VERSION 5.7 ;
BUSBITCHARS "[]" ;
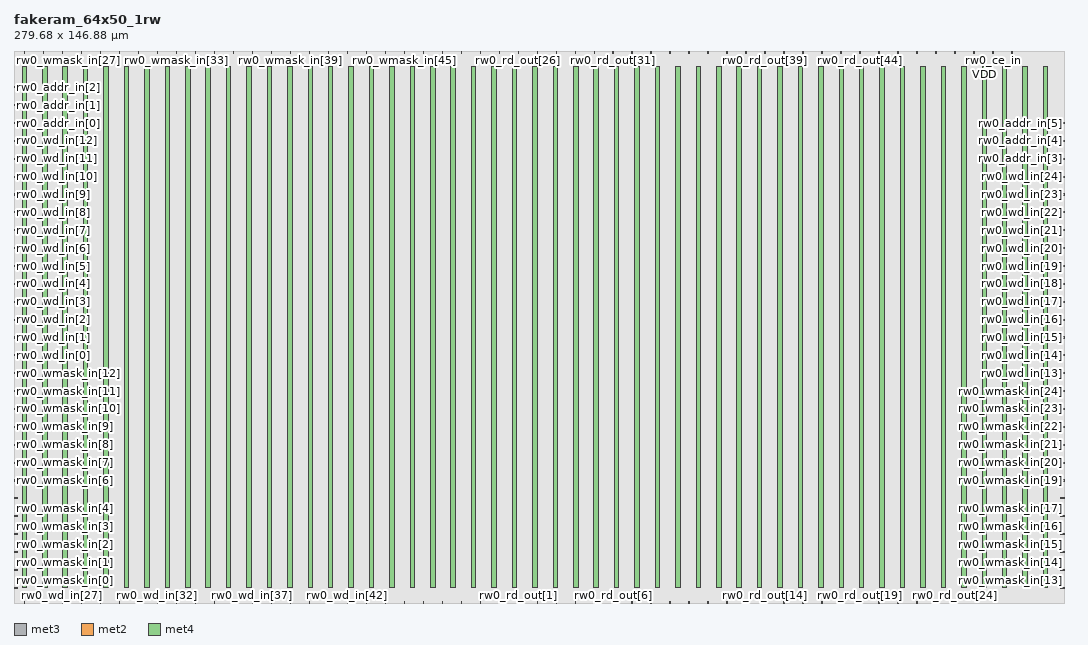
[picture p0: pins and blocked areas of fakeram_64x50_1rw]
MACRO fakeram_64x50_1rw
  FOREIGN fakeram_64x50_1rw 0 0 ;
  SYMMETRY X Y R90 ;
  SIZE 279.680 BY 146.880 ;
  CLASS BLOCK ;
  PIN rw0_wmask_in[0]
    DIRECTION INPUT ;
    USE SIGNAL ;
    SHAPE ABUTMENT ;
    PORT
      LAYER met3 ;
      RECT 0.000 3.930 0.900 4.230 ;
    END
  END rw0_wmask_in[0]
  PIN rw0_wmask_in[1]
    DIRECTION INPUT ;
    USE SIGNAL ;
    SHAPE ABUTMENT ;
    PORT
      LAYER met3 ;
      RECT 0.000 8.690 0.900 8.990 ;
    END
  END rw0_wmask_in[1]
  PIN rw0_wmask_in[2]
    DIRECTION INPUT ;
    USE SIGNAL ;
    SHAPE ABUTMENT ;
    PORT
      LAYER met3 ;
      RECT 0.000 13.450 0.900 13.750 ;
    END
  END rw0_wmask_in[2]
  PIN rw0_wmask_in[3]
    DIRECTION INPUT ;
    USE SIGNAL ;
    SHAPE ABUTMENT ;
    PORT
      LAYER met3 ;
      RECT 0.000 18.210 0.900 18.510 ;
    END
  END rw0_wmask_in[3]
  PIN rw0_wmask_in[4]
    DIRECTION INPUT ;
    USE SIGNAL ;
    SHAPE ABUTMENT ;
    PORT
      LAYER met3 ;
      RECT 0.000 22.970 0.900 23.270 ;
    END
  END rw0_wmask_in[4]
  PIN rw0_wmask_in[5]
    DIRECTION INPUT ;
    USE SIGNAL ;
    SHAPE ABUTMENT ;
    PORT
      LAYER met3 ;
      RECT 0.000 27.730 0.900 28.030 ;
    END
  END rw0_wmask_in[5]
  PIN rw0_wmask_in[6]
    DIRECTION INPUT ;
    USE SIGNAL ;
    SHAPE ABUTMENT ;
    PORT
      LAYER met3 ;
      RECT 0.000 32.490 0.900 32.790 ;
    END
  END rw0_wmask_in[6]
  PIN rw0_wmask_in[7]
    DIRECTION INPUT ;
    USE SIGNAL ;
    SHAPE ABUTMENT ;
    PORT
      LAYER met3 ;
      RECT 0.000 37.250 0.900 37.550 ;
    END
  END rw0_wmask_in[7]
  PIN rw0_wmask_in[8]
    DIRECTION INPUT ;
    USE SIGNAL ;
    SHAPE ABUTMENT ;
    PORT
      LAYER met3 ;
      RECT 0.000 42.010 0.900 42.310 ;
    END
  END rw0_wmask_in[8]
  PIN rw0_wmask_in[9]
    DIRECTION INPUT ;
    USE SIGNAL ;
    SHAPE ABUTMENT ;
    PORT
      LAYER met3 ;
      RECT 0.000 46.770 0.900 47.070 ;
    END
  END rw0_wmask_in[9]
  PIN rw0_wmask_in[10]
    DIRECTION INPUT ;
    USE SIGNAL ;
    SHAPE ABUTMENT ;
    PORT
      LAYER met3 ;
      RECT 0.000 51.530 0.900 51.830 ;
    END
  END rw0_wmask_in[10]
  PIN rw0_wmask_in[11]
    DIRECTION INPUT ;
    USE SIGNAL ;
    SHAPE ABUTMENT ;
    PORT
      LAYER met3 ;
      RECT 0.000 56.290 0.900 56.590 ;
    END
  END rw0_wmask_in[11]
  PIN rw0_wmask_in[12]
    DIRECTION INPUT ;
    USE SIGNAL ;
    SHAPE ABUTMENT ;
    PORT
      LAYER met3 ;
      RECT 0.000 61.050 0.900 61.350 ;
    END
  END rw0_wmask_in[12]
  PIN rw0_wmask_in[13]
    DIRECTION INPUT ;
    USE SIGNAL ;
    SHAPE ABUTMENT ;
    PORT
      LAYER met3 ;
      RECT 278.780 3.930 279.680 4.230 ;
    END
  END rw0_wmask_in[13]
  PIN rw0_wmask_in[14]
    DIRECTION INPUT ;
    USE SIGNAL ;
    SHAPE ABUTMENT ;
    PORT
      LAYER met3 ;
      RECT 278.780 8.690 279.680 8.990 ;
    END
  END rw0_wmask_in[14]
  PIN rw0_wmask_in[15]
    DIRECTION INPUT ;
    USE SIGNAL ;
    SHAPE ABUTMENT ;
    PORT
      LAYER met3 ;
      RECT 278.780 13.450 279.680 13.750 ;
    END
  END rw0_wmask_in[15]
  PIN rw0_wmask_in[16]
    DIRECTION INPUT ;
    USE SIGNAL ;
    SHAPE ABUTMENT ;
    PORT
      LAYER met3 ;
      RECT 278.780 18.210 279.680 18.510 ;
    END
  END rw0_wmask_in[16]
  PIN rw0_wmask_in[17]
    DIRECTION INPUT ;
    USE SIGNAL ;
    SHAPE ABUTMENT ;
    PORT
      LAYER met3 ;
      RECT 278.780 22.970 279.680 23.270 ;
    END
  END rw0_wmask_in[17]
  PIN rw0_wmask_in[18]
    DIRECTION INPUT ;
    USE SIGNAL ;
    SHAPE ABUTMENT ;
    PORT
      LAYER met3 ;
      RECT 278.780 27.730 279.680 28.030 ;
    END
  END rw0_wmask_in[18]
  PIN rw0_wmask_in[19]
    DIRECTION INPUT ;
    USE SIGNAL ;
    SHAPE ABUTMENT ;
    PORT
      LAYER met3 ;
      RECT 278.780 32.490 279.680 32.790 ;
    END
  END rw0_wmask_in[19]
  PIN rw0_wmask_in[20]
    DIRECTION INPUT ;
    USE SIGNAL ;
    SHAPE ABUTMENT ;
    PORT
      LAYER met3 ;
      RECT 278.780 37.250 279.680 37.550 ;
    END
  END rw0_wmask_in[20]
  PIN rw0_wmask_in[21]
    DIRECTION INPUT ;
    USE SIGNAL ;
    SHAPE ABUTMENT ;
    PORT
      LAYER met3 ;
      RECT 278.780 42.010 279.680 42.310 ;
    END
  END rw0_wmask_in[21]
  PIN rw0_wmask_in[22]
    DIRECTION INPUT ;
    USE SIGNAL ;
    SHAPE ABUTMENT ;
    PORT
      LAYER met3 ;
      RECT 278.780 46.770 279.680 47.070 ;
    END
  END rw0_wmask_in[22]
  PIN rw0_wmask_in[23]
    DIRECTION INPUT ;
    USE SIGNAL ;
    SHAPE ABUTMENT ;
    PORT
      LAYER met3 ;
      RECT 278.780 51.530 279.680 51.830 ;
    END
  END rw0_wmask_in[23]
  PIN rw0_wmask_in[24]
    DIRECTION INPUT ;
    USE SIGNAL ;
    SHAPE ABUTMENT ;
    PORT
      LAYER met3 ;
      RECT 278.780 56.290 279.680 56.590 ;
    END
  END rw0_wmask_in[24]
  PIN rw0_wmask_in[25]
    DIRECTION INPUT ;
    USE SIGNAL ;
    SHAPE ABUTMENT ;
    PORT
      LAYER met2 ;
      RECT 2.690 146.460 2.830 146.880 ;
    END
  END rw0_wmask_in[25]
  PIN rw0_wmask_in[26]
    DIRECTION INPUT ;
    USE SIGNAL ;
    SHAPE ABUTMENT ;
    PORT
      LAYER met2 ;
      RECT 7.750 146.460 7.890 146.880 ;
    END
  END rw0_wmask_in[26]
  PIN rw0_wmask_in[27]
    DIRECTION INPUT ;
    USE SIGNAL ;
    SHAPE ABUTMENT ;
    PORT
      LAYER met2 ;
      RECT 12.810 146.460 12.950 146.880 ;
    END
  END rw0_wmask_in[27]
  PIN rw0_wmask_in[28]
    DIRECTION INPUT ;
    USE SIGNAL ;
    SHAPE ABUTMENT ;
    PORT
      LAYER met2 ;
      RECT 17.870 146.460 18.010 146.880 ;
    END
  END rw0_wmask_in[28]
  PIN rw0_wmask_in[29]
    DIRECTION INPUT ;
    USE SIGNAL ;
    SHAPE ABUTMENT ;
    PORT
      LAYER met2 ;
      RECT 22.930 146.460 23.070 146.880 ;
    END
  END rw0_wmask_in[29]
  PIN rw0_wmask_in[30]
    DIRECTION INPUT ;
    USE SIGNAL ;
    SHAPE ABUTMENT ;
    PORT
      LAYER met2 ;
      RECT 27.990 146.460 28.130 146.880 ;
    END
  END rw0_wmask_in[30]
  PIN rw0_wmask_in[31]
    DIRECTION INPUT ;
    USE SIGNAL ;
    SHAPE ABUTMENT ;
    PORT
      LAYER met2 ;
      RECT 33.050 146.460 33.190 146.880 ;
    END
  END rw0_wmask_in[31]
  PIN rw0_wmask_in[32]
    DIRECTION INPUT ;
    USE SIGNAL ;
    SHAPE ABUTMENT ;
    PORT
      LAYER met2 ;
      RECT 38.110 146.460 38.250 146.880 ;
    END
  END rw0_wmask_in[32]
  PIN rw0_wmask_in[33]
    DIRECTION INPUT ;
    USE SIGNAL ;
    SHAPE ABUTMENT ;
    PORT
      LAYER met2 ;
      RECT 43.170 146.460 43.310 146.880 ;
    END
  END rw0_wmask_in[33]
  PIN rw0_wmask_in[34]
    DIRECTION INPUT ;
    USE SIGNAL ;
    SHAPE ABUTMENT ;
    PORT
      LAYER met2 ;
      RECT 48.230 146.460 48.370 146.880 ;
    END
  END rw0_wmask_in[34]
  PIN rw0_wmask_in[35]
    DIRECTION INPUT ;
    USE SIGNAL ;
    SHAPE ABUTMENT ;
    PORT
      LAYER met2 ;
      RECT 53.290 146.460 53.430 146.880 ;
    END
  END rw0_wmask_in[35]
  PIN rw0_wmask_in[36]
    DIRECTION INPUT ;
    USE SIGNAL ;
    SHAPE ABUTMENT ;
    PORT
      LAYER met2 ;
      RECT 58.350 146.460 58.490 146.880 ;
    END
  END rw0_wmask_in[36]
  PIN rw0_wmask_in[37]
    DIRECTION INPUT ;
    USE SIGNAL ;
    SHAPE ABUTMENT ;
    PORT
      LAYER met2 ;
      RECT 63.410 146.460 63.550 146.880 ;
    END
  END rw0_wmask_in[37]
  PIN rw0_wmask_in[38]
    DIRECTION INPUT ;
    USE SIGNAL ;
    SHAPE ABUTMENT ;
    PORT
      LAYER met2 ;
      RECT 68.470 146.460 68.610 146.880 ;
    END
  END rw0_wmask_in[38]
  PIN rw0_wmask_in[39]
    DIRECTION INPUT ;
    USE SIGNAL ;
    SHAPE ABUTMENT ;
    PORT
      LAYER met2 ;
      RECT 73.530 146.460 73.670 146.880 ;
    END
  END rw0_wmask_in[39]
  PIN rw0_wmask_in[40]
    DIRECTION INPUT ;
    USE SIGNAL ;
    SHAPE ABUTMENT ;
    PORT
      LAYER met2 ;
      RECT 78.590 146.460 78.730 146.880 ;
    END
  END rw0_wmask_in[40]
  PIN rw0_wmask_in[41]
    DIRECTION INPUT ;
    USE SIGNAL ;
    SHAPE ABUTMENT ;
    PORT
      LAYER met2 ;
      RECT 83.650 146.460 83.790 146.880 ;
    END
  END rw0_wmask_in[41]
  PIN rw0_wmask_in[42]
    DIRECTION INPUT ;
    USE SIGNAL ;
    SHAPE ABUTMENT ;
    PORT
      LAYER met2 ;
      RECT 88.710 146.460 88.850 146.880 ;
    END
  END rw0_wmask_in[42]
  PIN rw0_wmask_in[43]
    DIRECTION INPUT ;
    USE SIGNAL ;
    SHAPE ABUTMENT ;
    PORT
      LAYER met2 ;
      RECT 93.770 146.460 93.910 146.880 ;
    END
  END rw0_wmask_in[43]
  PIN rw0_wmask_in[44]
    DIRECTION INPUT ;
    USE SIGNAL ;
    SHAPE ABUTMENT ;
    PORT
      LAYER met2 ;
      RECT 98.830 146.460 98.970 146.880 ;
    END
  END rw0_wmask_in[44]
  PIN rw0_wmask_in[45]
    DIRECTION INPUT ;
    USE SIGNAL ;
    SHAPE ABUTMENT ;
    PORT
      LAYER met2 ;
      RECT 103.890 146.460 104.030 146.880 ;
    END
  END rw0_wmask_in[45]
  PIN rw0_wmask_in[46]
    DIRECTION INPUT ;
    USE SIGNAL ;
    SHAPE ABUTMENT ;
    PORT
      LAYER met2 ;
      RECT 108.950 146.460 109.090 146.880 ;
    END
  END rw0_wmask_in[46]
  PIN rw0_wmask_in[47]
    DIRECTION INPUT ;
    USE SIGNAL ;
    SHAPE ABUTMENT ;
    PORT
      LAYER met2 ;
      RECT 114.010 146.460 114.150 146.880 ;
    END
  END rw0_wmask_in[47]
  PIN rw0_wmask_in[48]
    DIRECTION INPUT ;
    USE SIGNAL ;
    SHAPE ABUTMENT ;
    PORT
      LAYER met2 ;
      RECT 119.070 146.460 119.210 146.880 ;
    END
  END rw0_wmask_in[48]
  PIN rw0_wmask_in[49]
    DIRECTION INPUT ;
    USE SIGNAL ;
    SHAPE ABUTMENT ;
    PORT
      LAYER met2 ;
      RECT 124.130 146.460 124.270 146.880 ;
    END
  END rw0_wmask_in[49]
  PIN rw0_wd_in[0]
    DIRECTION INPUT ;
    USE SIGNAL ;
    SHAPE ABUTMENT ;
    PORT
      LAYER met3 ;
      RECT 0.000 65.810 0.900 66.110 ;
    END
  END rw0_wd_in[0]
  PIN rw0_wd_in[1]
    DIRECTION INPUT ;
    USE SIGNAL ;
    SHAPE ABUTMENT ;
    PORT
      LAYER met3 ;
      RECT 0.000 70.570 0.900 70.870 ;
    END
  END rw0_wd_in[1]
  PIN rw0_wd_in[2]
    DIRECTION INPUT ;
    USE SIGNAL ;
    SHAPE ABUTMENT ;
    PORT
      LAYER met3 ;
      RECT 0.000 75.330 0.900 75.630 ;
    END
  END rw0_wd_in[2]
  PIN rw0_wd_in[3]
    DIRECTION INPUT ;
    USE SIGNAL ;
    SHAPE ABUTMENT ;
    PORT
      LAYER met3 ;
      RECT 0.000 80.090 0.900 80.390 ;
    END
  END rw0_wd_in[3]
  PIN rw0_wd_in[4]
    DIRECTION INPUT ;
    USE SIGNAL ;
    SHAPE ABUTMENT ;
    PORT
      LAYER met3 ;
      RECT 0.000 84.850 0.900 85.150 ;
    END
  END rw0_wd_in[4]
  PIN rw0_wd_in[5]
    DIRECTION INPUT ;
    USE SIGNAL ;
    SHAPE ABUTMENT ;
    PORT
      LAYER met3 ;
      RECT 0.000 89.610 0.900 89.910 ;
    END
  END rw0_wd_in[5]
  PIN rw0_wd_in[6]
    DIRECTION INPUT ;
    USE SIGNAL ;
    SHAPE ABUTMENT ;
    PORT
      LAYER met3 ;
      RECT 0.000 94.370 0.900 94.670 ;
    END
  END rw0_wd_in[6]
  PIN rw0_wd_in[7]
    DIRECTION INPUT ;
    USE SIGNAL ;
    SHAPE ABUTMENT ;
    PORT
      LAYER met3 ;
      RECT 0.000 99.130 0.900 99.430 ;
    END
  END rw0_wd_in[7]
  PIN rw0_wd_in[8]
    DIRECTION INPUT ;
    USE SIGNAL ;
    SHAPE ABUTMENT ;
    PORT
      LAYER met3 ;
      RECT 0.000 103.890 0.900 104.190 ;
    END
  END rw0_wd_in[8]
  PIN rw0_wd_in[9]
    DIRECTION INPUT ;
    USE SIGNAL ;
    SHAPE ABUTMENT ;
    PORT
      LAYER met3 ;
      RECT 0.000 108.650 0.900 108.950 ;
    END
  END rw0_wd_in[9]
  PIN rw0_wd_in[10]
    DIRECTION INPUT ;
    USE SIGNAL ;
    SHAPE ABUTMENT ;
    PORT
      LAYER met3 ;
      RECT 0.000 113.410 0.900 113.710 ;
    END
  END rw0_wd_in[10]
  PIN rw0_wd_in[11]
    DIRECTION INPUT ;
    USE SIGNAL ;
    SHAPE ABUTMENT ;
    PORT
      LAYER met3 ;
      RECT 0.000 118.170 0.900 118.470 ;
    END
  END rw0_wd_in[11]
  PIN rw0_wd_in[12]
    DIRECTION INPUT ;
    USE SIGNAL ;
    SHAPE ABUTMENT ;
    PORT
      LAYER met3 ;
      RECT 0.000 122.930 0.900 123.230 ;
    END
  END rw0_wd_in[12]
  PIN rw0_wd_in[13]
    DIRECTION INPUT ;
    USE SIGNAL ;
    SHAPE ABUTMENT ;
    PORT
      LAYER met3 ;
      RECT 278.780 61.050 279.680 61.350 ;
    END
  END rw0_wd_in[13]
  PIN rw0_wd_in[14]
    DIRECTION INPUT ;
    USE SIGNAL ;
    SHAPE ABUTMENT ;
    PORT
      LAYER met3 ;
      RECT 278.780 65.810 279.680 66.110 ;
    END
  END rw0_wd_in[14]
  PIN rw0_wd_in[15]
    DIRECTION INPUT ;
    USE SIGNAL ;
    SHAPE ABUTMENT ;
    PORT
      LAYER met3 ;
      RECT 278.780 70.570 279.680 70.870 ;
    END
  END rw0_wd_in[15]
  PIN rw0_wd_in[16]
    DIRECTION INPUT ;
    USE SIGNAL ;
    SHAPE ABUTMENT ;
    PORT
      LAYER met3 ;
      RECT 278.780 75.330 279.680 75.630 ;
    END
  END rw0_wd_in[16]
  PIN rw0_wd_in[17]
    DIRECTION INPUT ;
    USE SIGNAL ;
    SHAPE ABUTMENT ;
    PORT
      LAYER met3 ;
      RECT 278.780 80.090 279.680 80.390 ;
    END
  END rw0_wd_in[17]
  PIN rw0_wd_in[18]
    DIRECTION INPUT ;
    USE SIGNAL ;
    SHAPE ABUTMENT ;
    PORT
      LAYER met3 ;
      RECT 278.780 84.850 279.680 85.150 ;
    END
  END rw0_wd_in[18]
  PIN rw0_wd_in[19]
    DIRECTION INPUT ;
    USE SIGNAL ;
    SHAPE ABUTMENT ;
    PORT
      LAYER met3 ;
      RECT 278.780 89.610 279.680 89.910 ;
    END
  END rw0_wd_in[19]
  PIN rw0_wd_in[20]
    DIRECTION INPUT ;
    USE SIGNAL ;
    SHAPE ABUTMENT ;
    PORT
      LAYER met3 ;
      RECT 278.780 94.370 279.680 94.670 ;
    END
  END rw0_wd_in[20]
  PIN rw0_wd_in[21]
    DIRECTION INPUT ;
    USE SIGNAL ;
    SHAPE ABUTMENT ;
    PORT
      LAYER met3 ;
      RECT 278.780 99.130 279.680 99.430 ;
    END
  END rw0_wd_in[21]
  PIN rw0_wd_in[22]
    DIRECTION INPUT ;
    USE SIGNAL ;
    SHAPE ABUTMENT ;
    PORT
      LAYER met3 ;
      RECT 278.780 103.890 279.680 104.190 ;
    END
  END rw0_wd_in[22]
  PIN rw0_wd_in[23]
    DIRECTION INPUT ;
    USE SIGNAL ;
    SHAPE ABUTMENT ;
    PORT
      LAYER met3 ;
      RECT 278.780 108.650 279.680 108.950 ;
    END
  END rw0_wd_in[23]
  PIN rw0_wd_in[24]
    DIRECTION INPUT ;
    USE SIGNAL ;
    SHAPE ABUTMENT ;
    PORT
      LAYER met3 ;
      RECT 278.780 113.410 279.680 113.710 ;
    END
  END rw0_wd_in[24]
  PIN rw0_wd_in[25]
    DIRECTION INPUT ;
    USE SIGNAL ;
    SHAPE ABUTMENT ;
    PORT
      LAYER met2 ;
      RECT 2.690 0.000 2.830 0.420 ;
    END
  END rw0_wd_in[25]
  PIN rw0_wd_in[26]
    DIRECTION INPUT ;
    USE SIGNAL ;
    SHAPE ABUTMENT ;
    PORT
      LAYER met2 ;
      RECT 7.750 0.000 7.890 0.420 ;
    END
  END rw0_wd_in[26]
  PIN rw0_wd_in[27]
    DIRECTION INPUT ;
    USE SIGNAL ;
    SHAPE ABUTMENT ;
    PORT
      LAYER met2 ;
      RECT 12.810 0.000 12.950 0.420 ;
    END
  END rw0_wd_in[27]
  PIN rw0_wd_in[28]
    DIRECTION INPUT ;
    USE SIGNAL ;
    SHAPE ABUTMENT ;
    PORT
      LAYER met2 ;
      RECT 17.870 0.000 18.010 0.420 ;
    END
  END rw0_wd_in[28]
  PIN rw0_wd_in[29]
    DIRECTION INPUT ;
    USE SIGNAL ;
    SHAPE ABUTMENT ;
    PORT
      LAYER met2 ;
      RECT 22.930 0.000 23.070 0.420 ;
    END
  END rw0_wd_in[29]
  PIN rw0_wd_in[30]
    DIRECTION INPUT ;
    USE SIGNAL ;
    SHAPE ABUTMENT ;
    PORT
      LAYER met2 ;
      RECT 27.990 0.000 28.130 0.420 ;
    END
  END rw0_wd_in[30]
  PIN rw0_wd_in[31]
    DIRECTION INPUT ;
    USE SIGNAL ;
    SHAPE ABUTMENT ;
    PORT
      LAYER met2 ;
      RECT 33.050 0.000 33.190 0.420 ;
    END
  END rw0_wd_in[31]
  PIN rw0_wd_in[32]
    DIRECTION INPUT ;
    USE SIGNAL ;
    SHAPE ABUTMENT ;
    PORT
      LAYER met2 ;
      RECT 38.110 0.000 38.250 0.420 ;
    END
  END rw0_wd_in[32]
  PIN rw0_wd_in[33]
    DIRECTION INPUT ;
    USE SIGNAL ;
    SHAPE ABUTMENT ;
    PORT
      LAYER met2 ;
      RECT 43.170 0.000 43.310 0.420 ;
    END
  END rw0_wd_in[33]
  PIN rw0_wd_in[34]
    DIRECTION INPUT ;
    USE SIGNAL ;
    SHAPE ABUTMENT ;
    PORT
      LAYER met2 ;
      RECT 48.230 0.000 48.370 0.420 ;
    END
  END rw0_wd_in[34]
  PIN rw0_wd_in[35]
    DIRECTION INPUT ;
    USE SIGNAL ;
    SHAPE ABUTMENT ;
    PORT
      LAYER met2 ;
      RECT 53.290 0.000 53.430 0.420 ;
    END
  END rw0_wd_in[35]
  PIN rw0_wd_in[36]
    DIRECTION INPUT ;
    USE SIGNAL ;
    SHAPE ABUTMENT ;
    PORT
      LAYER met2 ;
      RECT 58.350 0.000 58.490 0.420 ;
    END
  END rw0_wd_in[36]
  PIN rw0_wd_in[37]
    DIRECTION INPUT ;
    USE SIGNAL ;
    SHAPE ABUTMENT ;
    PORT
      LAYER met2 ;
      RECT 63.410 0.000 63.550 0.420 ;
    END
  END rw0_wd_in[37]
  PIN rw0_wd_in[38]
    DIRECTION INPUT ;
    USE SIGNAL ;
    SHAPE ABUTMENT ;
    PORT
      LAYER met2 ;
      RECT 68.470 0.000 68.610 0.420 ;
    END
  END rw0_wd_in[38]
  PIN rw0_wd_in[39]
    DIRECTION INPUT ;
    USE SIGNAL ;
    SHAPE ABUTMENT ;
    PORT
      LAYER met2 ;
      RECT 73.530 0.000 73.670 0.420 ;
    END
  END rw0_wd_in[39]
  PIN rw0_wd_in[40]
    DIRECTION INPUT ;
    USE SIGNAL ;
    SHAPE ABUTMENT ;
    PORT
      LAYER met2 ;
      RECT 78.590 0.000 78.730 0.420 ;
    END
  END rw0_wd_in[40]
  PIN rw0_wd_in[41]
    DIRECTION INPUT ;
    USE SIGNAL ;
    SHAPE ABUTMENT ;
    PORT
      LAYER met2 ;
      RECT 83.650 0.000 83.790 0.420 ;
    END
  END rw0_wd_in[41]
  PIN rw0_wd_in[42]
    DIRECTION INPUT ;
    USE SIGNAL ;
    SHAPE ABUTMENT ;
    PORT
      LAYER met2 ;
      RECT 88.710 0.000 88.850 0.420 ;
    END
  END rw0_wd_in[42]
  PIN rw0_wd_in[43]
    DIRECTION INPUT ;
    USE SIGNAL ;
    SHAPE ABUTMENT ;
    PORT
      LAYER met2 ;
      RECT 93.770 0.000 93.910 0.420 ;
    END
  END rw0_wd_in[43]
  PIN rw0_wd_in[44]
    DIRECTION INPUT ;
    USE SIGNAL ;
    SHAPE ABUTMENT ;
    PORT
      LAYER met2 ;
      RECT 98.830 0.000 98.970 0.420 ;
    END
  END rw0_wd_in[44]
  PIN rw0_wd_in[45]
    DIRECTION INPUT ;
    USE SIGNAL ;
    SHAPE ABUTMENT ;
    PORT
      LAYER met2 ;
      RECT 103.890 0.000 104.030 0.420 ;
    END
  END rw0_wd_in[45]
  PIN rw0_wd_in[46]
    DIRECTION INPUT ;
    USE SIGNAL ;
    SHAPE ABUTMENT ;
    PORT
      LAYER met2 ;
      RECT 108.950 0.000 109.090 0.420 ;
    END
  END rw0_wd_in[46]
  PIN rw0_wd_in[47]
    DIRECTION INPUT ;
    USE SIGNAL ;
    SHAPE ABUTMENT ;
    PORT
      LAYER met2 ;
      RECT 114.010 0.000 114.150 0.420 ;
    END
  END rw0_wd_in[47]
  PIN rw0_wd_in[48]
    DIRECTION INPUT ;
    USE SIGNAL ;
    SHAPE ABUTMENT ;
    PORT
      LAYER met2 ;
      RECT 119.070 0.000 119.210 0.420 ;
    END
  END rw0_wd_in[48]
  PIN rw0_wd_in[49]
    DIRECTION INPUT ;
    USE SIGNAL ;
    SHAPE ABUTMENT ;
    PORT
      LAYER met2 ;
      RECT 124.130 0.000 124.270 0.420 ;
    END
  END rw0_wd_in[49]
  PIN rw0_rd_out[0]
    DIRECTION OUTPUT ;
    USE SIGNAL ;
    SHAPE ABUTMENT ;
    PORT
      LAYER met2 ;
      RECT 129.190 0.000 129.330 0.420 ;
    END
  END rw0_rd_out[0]
  PIN rw0_rd_out[1]
    DIRECTION OUTPUT ;
    USE SIGNAL ;
    SHAPE ABUTMENT ;
    PORT
      LAYER met2 ;
      RECT 134.250 0.000 134.390 0.420 ;
    END
  END rw0_rd_out[1]
  PIN rw0_rd_out[2]
    DIRECTION OUTPUT ;
    USE SIGNAL ;
    SHAPE ABUTMENT ;
    PORT
      LAYER met2 ;
      RECT 139.310 0.000 139.450 0.420 ;
    END
  END rw0_rd_out[2]
  PIN rw0_rd_out[3]
    DIRECTION OUTPUT ;
    USE SIGNAL ;
    SHAPE ABUTMENT ;
    PORT
      LAYER met2 ;
      RECT 144.370 0.000 144.510 0.420 ;
    END
  END rw0_rd_out[3]
  PIN rw0_rd_out[4]
    DIRECTION OUTPUT ;
    USE SIGNAL ;
    SHAPE ABUTMENT ;
    PORT
      LAYER met2 ;
      RECT 149.430 0.000 149.570 0.420 ;
    END
  END rw0_rd_out[4]
  PIN rw0_rd_out[5]
    DIRECTION OUTPUT ;
    USE SIGNAL ;
    SHAPE ABUTMENT ;
    PORT
      LAYER met2 ;
      RECT 154.490 0.000 154.630 0.420 ;
    END
  END rw0_rd_out[5]
  PIN rw0_rd_out[6]
    DIRECTION OUTPUT ;
    USE SIGNAL ;
    SHAPE ABUTMENT ;
    PORT
      LAYER met2 ;
      RECT 159.550 0.000 159.690 0.420 ;
    END
  END rw0_rd_out[6]
  PIN rw0_rd_out[7]
    DIRECTION OUTPUT ;
    USE SIGNAL ;
    SHAPE ABUTMENT ;
    PORT
      LAYER met2 ;
      RECT 164.610 0.000 164.750 0.420 ;
    END
  END rw0_rd_out[7]
  PIN rw0_rd_out[8]
    DIRECTION OUTPUT ;
    USE SIGNAL ;
    SHAPE ABUTMENT ;
    PORT
      LAYER met2 ;
      RECT 169.670 0.000 169.810 0.420 ;
    END
  END rw0_rd_out[8]
  PIN rw0_rd_out[9]
    DIRECTION OUTPUT ;
    USE SIGNAL ;
    SHAPE ABUTMENT ;
    PORT
      LAYER met2 ;
      RECT 174.730 0.000 174.870 0.420 ;
    END
  END rw0_rd_out[9]
  PIN rw0_rd_out[10]
    DIRECTION OUTPUT ;
    USE SIGNAL ;
    SHAPE ABUTMENT ;
    PORT
      LAYER met2 ;
      RECT 179.790 0.000 179.930 0.420 ;
    END
  END rw0_rd_out[10]
  PIN rw0_rd_out[11]
    DIRECTION OUTPUT ;
    USE SIGNAL ;
    SHAPE ABUTMENT ;
    PORT
      LAYER met2 ;
      RECT 184.850 0.000 184.990 0.420 ;
    END
  END rw0_rd_out[11]
  PIN rw0_rd_out[12]
    DIRECTION OUTPUT ;
    USE SIGNAL ;
    SHAPE ABUTMENT ;
    PORT
      LAYER met2 ;
      RECT 189.910 0.000 190.050 0.420 ;
    END
  END rw0_rd_out[12]
  PIN rw0_rd_out[13]
    DIRECTION OUTPUT ;
    USE SIGNAL ;
    SHAPE ABUTMENT ;
    PORT
      LAYER met2 ;
      RECT 194.970 0.000 195.110 0.420 ;
    END
  END rw0_rd_out[13]
  PIN rw0_rd_out[14]
    DIRECTION OUTPUT ;
    USE SIGNAL ;
    SHAPE ABUTMENT ;
    PORT
      LAYER met2 ;
      RECT 200.030 0.000 200.170 0.420 ;
    END
  END rw0_rd_out[14]
  PIN rw0_rd_out[15]
    DIRECTION OUTPUT ;
    USE SIGNAL ;
    SHAPE ABUTMENT ;
    PORT
      LAYER met2 ;
      RECT 205.090 0.000 205.230 0.420 ;
    END
  END rw0_rd_out[15]
  PIN rw0_rd_out[16]
    DIRECTION OUTPUT ;
    USE SIGNAL ;
    SHAPE ABUTMENT ;
    PORT
      LAYER met2 ;
      RECT 210.150 0.000 210.290 0.420 ;
    END
  END rw0_rd_out[16]
  PIN rw0_rd_out[17]
    DIRECTION OUTPUT ;
    USE SIGNAL ;
    SHAPE ABUTMENT ;
    PORT
      LAYER met2 ;
      RECT 215.210 0.000 215.350 0.420 ;
    END
  END rw0_rd_out[17]
  PIN rw0_rd_out[18]
    DIRECTION OUTPUT ;
    USE SIGNAL ;
    SHAPE ABUTMENT ;
    PORT
      LAYER met2 ;
      RECT 220.270 0.000 220.410 0.420 ;
    END
  END rw0_rd_out[18]
  PIN rw0_rd_out[19]
    DIRECTION OUTPUT ;
    USE SIGNAL ;
    SHAPE ABUTMENT ;
    PORT
      LAYER met2 ;
      RECT 225.330 0.000 225.470 0.420 ;
    END
  END rw0_rd_out[19]
  PIN rw0_rd_out[20]
    DIRECTION OUTPUT ;
    USE SIGNAL ;
    SHAPE ABUTMENT ;
    PORT
      LAYER met2 ;
      RECT 230.390 0.000 230.530 0.420 ;
    END
  END rw0_rd_out[20]
  PIN rw0_rd_out[21]
    DIRECTION OUTPUT ;
    USE SIGNAL ;
    SHAPE ABUTMENT ;
    PORT
      LAYER met2 ;
      RECT 235.450 0.000 235.590 0.420 ;
    END
  END rw0_rd_out[21]
  PIN rw0_rd_out[22]
    DIRECTION OUTPUT ;
    USE SIGNAL ;
    SHAPE ABUTMENT ;
    PORT
      LAYER met2 ;
      RECT 240.510 0.000 240.650 0.420 ;
    END
  END rw0_rd_out[22]
  PIN rw0_rd_out[23]
    DIRECTION OUTPUT ;
    USE SIGNAL ;
    SHAPE ABUTMENT ;
    PORT
      LAYER met2 ;
      RECT 245.570 0.000 245.710 0.420 ;
    END
  END rw0_rd_out[23]
  PIN rw0_rd_out[24]
    DIRECTION OUTPUT ;
    USE SIGNAL ;
    SHAPE ABUTMENT ;
    PORT
      LAYER met2 ;
      RECT 250.630 0.000 250.770 0.420 ;
    END
  END rw0_rd_out[24]
  PIN rw0_rd_out[25]
    DIRECTION OUTPUT ;
    USE SIGNAL ;
    SHAPE ABUTMENT ;
    PORT
      LAYER met2 ;
      RECT 129.190 146.460 129.330 146.880 ;
    END
  END rw0_rd_out[25]
  PIN rw0_rd_out[26]
    DIRECTION OUTPUT ;
    USE SIGNAL ;
    SHAPE ABUTMENT ;
    PORT
      LAYER met2 ;
      RECT 134.250 146.460 134.390 146.880 ;
    END
  END rw0_rd_out[26]
  PIN rw0_rd_out[27]
    DIRECTION OUTPUT ;
    USE SIGNAL ;
    SHAPE ABUTMENT ;
    PORT
      LAYER met2 ;
      RECT 139.310 146.460 139.450 146.880 ;
    END
  END rw0_rd_out[27]
  PIN rw0_rd_out[28]
    DIRECTION OUTPUT ;
    USE SIGNAL ;
    SHAPE ABUTMENT ;
    PORT
      LAYER met2 ;
      RECT 144.370 146.460 144.510 146.880 ;
    END
  END rw0_rd_out[28]
  PIN rw0_rd_out[29]
    DIRECTION OUTPUT ;
    USE SIGNAL ;
    SHAPE ABUTMENT ;
    PORT
      LAYER met2 ;
      RECT 149.430 146.460 149.570 146.880 ;
    END
  END rw0_rd_out[29]
  PIN rw0_rd_out[30]
    DIRECTION OUTPUT ;
    USE SIGNAL ;
    SHAPE ABUTMENT ;
    PORT
      LAYER met2 ;
      RECT 154.490 146.460 154.630 146.880 ;
    END
  END rw0_rd_out[30]
  PIN rw0_rd_out[31]
    DIRECTION OUTPUT ;
    USE SIGNAL ;
    SHAPE ABUTMENT ;
    PORT
      LAYER met2 ;
      RECT 159.550 146.460 159.690 146.880 ;
    END
  END rw0_rd_out[31]
  PIN rw0_rd_out[32]
    DIRECTION OUTPUT ;
    USE SIGNAL ;
    SHAPE ABUTMENT ;
    PORT
      LAYER met2 ;
      RECT 164.610 146.460 164.750 146.880 ;
    END
  END rw0_rd_out[32]
  PIN rw0_rd_out[33]
    DIRECTION OUTPUT ;
    USE SIGNAL ;
    SHAPE ABUTMENT ;
    PORT
      LAYER met2 ;
      RECT 169.670 146.460 169.810 146.880 ;
    END
  END rw0_rd_out[33]
  PIN rw0_rd_out[34]
    DIRECTION OUTPUT ;
    USE SIGNAL ;
    SHAPE ABUTMENT ;
    PORT
      LAYER met2 ;
      RECT 174.730 146.460 174.870 146.880 ;
    END
  END rw0_rd_out[34]
  PIN rw0_rd_out[35]
    DIRECTION OUTPUT ;
    USE SIGNAL ;
    SHAPE ABUTMENT ;
    PORT
      LAYER met2 ;
      RECT 179.790 146.460 179.930 146.880 ;
    END
  END rw0_rd_out[35]
  PIN rw0_rd_out[36]
    DIRECTION OUTPUT ;
    USE SIGNAL ;
    SHAPE ABUTMENT ;
    PORT
      LAYER met2 ;
      RECT 184.850 146.460 184.990 146.880 ;
    END
  END rw0_rd_out[36]
  PIN rw0_rd_out[37]
    DIRECTION OUTPUT ;
    USE SIGNAL ;
    SHAPE ABUTMENT ;
    PORT
      LAYER met2 ;
      RECT 189.910 146.460 190.050 146.880 ;
    END
  END rw0_rd_out[37]
  PIN rw0_rd_out[38]
    DIRECTION OUTPUT ;
    USE SIGNAL ;
    SHAPE ABUTMENT ;
    PORT
      LAYER met2 ;
      RECT 194.970 146.460 195.110 146.880 ;
    END
  END rw0_rd_out[38]
  PIN rw0_rd_out[39]
    DIRECTION OUTPUT ;
    USE SIGNAL ;
    SHAPE ABUTMENT ;
    PORT
      LAYER met2 ;
      RECT 200.030 146.460 200.170 146.880 ;
    END
  END rw0_rd_out[39]
  PIN rw0_rd_out[40]
    DIRECTION OUTPUT ;
    USE SIGNAL ;
    SHAPE ABUTMENT ;
    PORT
      LAYER met2 ;
      RECT 205.090 146.460 205.230 146.880 ;
    END
  END rw0_rd_out[40]
  PIN rw0_rd_out[41]
    DIRECTION OUTPUT ;
    USE SIGNAL ;
    SHAPE ABUTMENT ;
    PORT
      LAYER met2 ;
      RECT 210.150 146.460 210.290 146.880 ;
    END
  END rw0_rd_out[41]
  PIN rw0_rd_out[42]
    DIRECTION OUTPUT ;
    USE SIGNAL ;
    SHAPE ABUTMENT ;
    PORT
      LAYER met2 ;
      RECT 215.210 146.460 215.350 146.880 ;
    END
  END rw0_rd_out[42]
  PIN rw0_rd_out[43]
    DIRECTION OUTPUT ;
    USE SIGNAL ;
    SHAPE ABUTMENT ;
    PORT
      LAYER met2 ;
      RECT 220.270 146.460 220.410 146.880 ;
    END
  END rw0_rd_out[43]
  PIN rw0_rd_out[44]
    DIRECTION OUTPUT ;
    USE SIGNAL ;
    SHAPE ABUTMENT ;
    PORT
      LAYER met2 ;
      RECT 225.330 146.460 225.470 146.880 ;
    END
  END rw0_rd_out[44]
  PIN rw0_rd_out[45]
    DIRECTION OUTPUT ;
    USE SIGNAL ;
    SHAPE ABUTMENT ;
    PORT
      LAYER met2 ;
      RECT 230.390 146.460 230.530 146.880 ;
    END
  END rw0_rd_out[45]
  PIN rw0_rd_out[46]
    DIRECTION OUTPUT ;
    USE SIGNAL ;
    SHAPE ABUTMENT ;
    PORT
      LAYER met2 ;
      RECT 235.450 146.460 235.590 146.880 ;
    END
  END rw0_rd_out[46]
  PIN rw0_rd_out[47]
    DIRECTION OUTPUT ;
    USE SIGNAL ;
    SHAPE ABUTMENT ;
    PORT
      LAYER met2 ;
      RECT 240.510 146.460 240.650 146.880 ;
    END
  END rw0_rd_out[47]
  PIN rw0_rd_out[48]
    DIRECTION OUTPUT ;
    USE SIGNAL ;
    SHAPE ABUTMENT ;
    PORT
      LAYER met2 ;
      RECT 245.570 146.460 245.710 146.880 ;
    END
  END rw0_rd_out[48]
  PIN rw0_rd_out[49]
    DIRECTION OUTPUT ;
    USE SIGNAL ;
    SHAPE ABUTMENT ;
    PORT
      LAYER met2 ;
      RECT 250.630 146.460 250.770 146.880 ;
    END
  END rw0_rd_out[49]
  PIN rw0_addr_in[0]
    DIRECTION INPUT ;
    USE SIGNAL ;
    SHAPE ABUTMENT ;
    PORT
      LAYER met3 ;
      RECT 0.000 127.690 0.900 127.990 ;
    END
  END rw0_addr_in[0]
  PIN rw0_addr_in[1]
    DIRECTION INPUT ;
    USE SIGNAL ;
    SHAPE ABUTMENT ;
    PORT
      LAYER met3 ;
      RECT 0.000 132.450 0.900 132.750 ;
    END
  END rw0_addr_in[1]
  PIN rw0_addr_in[2]
    DIRECTION INPUT ;
    USE SIGNAL ;
    SHAPE ABUTMENT ;
    PORT
      LAYER met3 ;
      RECT 0.000 137.210 0.900 137.510 ;
    END
  END rw0_addr_in[2]
  PIN rw0_addr_in[3]
    DIRECTION INPUT ;
    USE SIGNAL ;
    SHAPE ABUTMENT ;
    PORT
      LAYER met3 ;
      RECT 278.780 118.170 279.680 118.470 ;
    END
  END rw0_addr_in[3]
  PIN rw0_addr_in[4]
    DIRECTION INPUT ;
    USE SIGNAL ;
    SHAPE ABUTMENT ;
    PORT
      LAYER met3 ;
      RECT 278.780 122.930 279.680 123.230 ;
    END
  END rw0_addr_in[4]
  PIN rw0_addr_in[5]
    DIRECTION INPUT ;
    USE SIGNAL ;
    SHAPE ABUTMENT ;
    PORT
      LAYER met3 ;
      RECT 278.780 127.690 279.680 127.990 ;
    END
  END rw0_addr_in[5]
  PIN rw0_we_in
    DIRECTION INPUT ;
    USE SIGNAL ;
    SHAPE ABUTMENT ;
    PORT
      LAYER met2 ;
      RECT 255.690 146.460 255.830 146.880 ;
    END
  END rw0_we_in
  PIN rw0_ce_in
    DIRECTION INPUT ;
    USE SIGNAL ;
    SHAPE ABUTMENT ;
    PORT
      LAYER met2 ;
      RECT 260.750 146.460 260.890 146.880 ;
    END
  END rw0_ce_in
  PIN rw0_clk
    DIRECTION INPUT ;
    USE SIGNAL ;
    SHAPE ABUTMENT ;
    PORT
      LAYER met2 ;
      RECT 265.810 146.460 265.950 146.880 ;
    END
  END rw0_clk
  PIN VSS
    DIRECTION INOUT ;
    USE GROUND ;
    PORT
      LAYER met4 ;
      RECT 2.160 4.080 3.360 142.800 ;
      RECT 13.040 4.080 14.240 142.800 ;
      RECT 23.920 4.080 25.120 142.800 ;
      RECT 34.800 4.080 36.000 142.800 ;
      RECT 45.680 4.080 46.880 142.800 ;
      RECT 56.560 4.080 57.760 142.800 ;
      RECT 67.440 4.080 68.640 142.800 ;
      RECT 78.320 4.080 79.520 142.800 ;
      RECT 89.200 4.080 90.400 142.800 ;
      RECT 100.080 4.080 101.280 142.800 ;
      RECT 110.960 4.080 112.160 142.800 ;
      RECT 121.840 4.080 123.040 142.800 ;
      RECT 132.720 4.080 133.920 142.800 ;
      RECT 143.600 4.080 144.800 142.800 ;
      RECT 154.480 4.080 155.680 142.800 ;
      RECT 165.360 4.080 166.560 142.800 ;
      RECT 176.240 4.080 177.440 142.800 ;
      RECT 187.120 4.080 188.320 142.800 ;
      RECT 198.000 4.080 199.200 142.800 ;
      RECT 208.880 4.080 210.080 142.800 ;
      RECT 219.760 4.080 220.960 142.800 ;
      RECT 230.640 4.080 231.840 142.800 ;
      RECT 241.520 4.080 242.720 142.800 ;
      RECT 252.400 4.080 253.600 142.800 ;
      RECT 263.280 4.080 264.480 142.800 ;
      RECT 274.160 4.080 275.360 142.800 ;
    END
  END VSS
  PIN VDD
    DIRECTION INOUT ;
    USE POWER ;
    PORT
      LAYER met4 ;
      RECT 7.600 4.080 8.800 142.800 ;
      RECT 18.480 4.080 19.680 142.800 ;
      RECT 29.360 4.080 30.560 142.800 ;
      RECT 40.240 4.080 41.440 142.800 ;
      RECT 51.120 4.080 52.320 142.800 ;
      RECT 62.000 4.080 63.200 142.800 ;
      RECT 72.880 4.080 74.080 142.800 ;
      RECT 83.760 4.080 84.960 142.800 ;
      RECT 94.640 4.080 95.840 142.800 ;
      RECT 105.520 4.080 106.720 142.800 ;
      RECT 116.400 4.080 117.600 142.800 ;
      RECT 127.280 4.080 128.480 142.800 ;
      RECT 138.160 4.080 139.360 142.800 ;
      RECT 149.040 4.080 150.240 142.800 ;
      RECT 159.920 4.080 161.120 142.800 ;
      RECT 170.800 4.080 172.000 142.800 ;
      RECT 181.680 4.080 182.880 142.800 ;
      RECT 192.560 4.080 193.760 142.800 ;
      RECT 203.440 4.080 204.640 142.800 ;
      RECT 214.320 4.080 215.520 142.800 ;
      RECT 225.200 4.080 226.400 142.800 ;
      RECT 236.080 4.080 237.280 142.800 ;
      RECT 246.960 4.080 248.160 142.800 ;
      RECT 257.840 4.080 259.040 142.800 ;
      RECT 268.720 4.080 269.920 142.800 ;
    END
  END VDD
  OBS
    LAYER met1 ;
    RECT 0 0 279.680 146.880 ;
    LAYER met2 ;
    RECT 0 0 279.680 146.880 ;
    LAYER met3 ;
    RECT 0 0 279.680 146.880 ;
    LAYER met4 ;
    RECT 0 0 279.680 146.880 ;
  END
END fakeram_64x50_1rw

END LIBRARY
